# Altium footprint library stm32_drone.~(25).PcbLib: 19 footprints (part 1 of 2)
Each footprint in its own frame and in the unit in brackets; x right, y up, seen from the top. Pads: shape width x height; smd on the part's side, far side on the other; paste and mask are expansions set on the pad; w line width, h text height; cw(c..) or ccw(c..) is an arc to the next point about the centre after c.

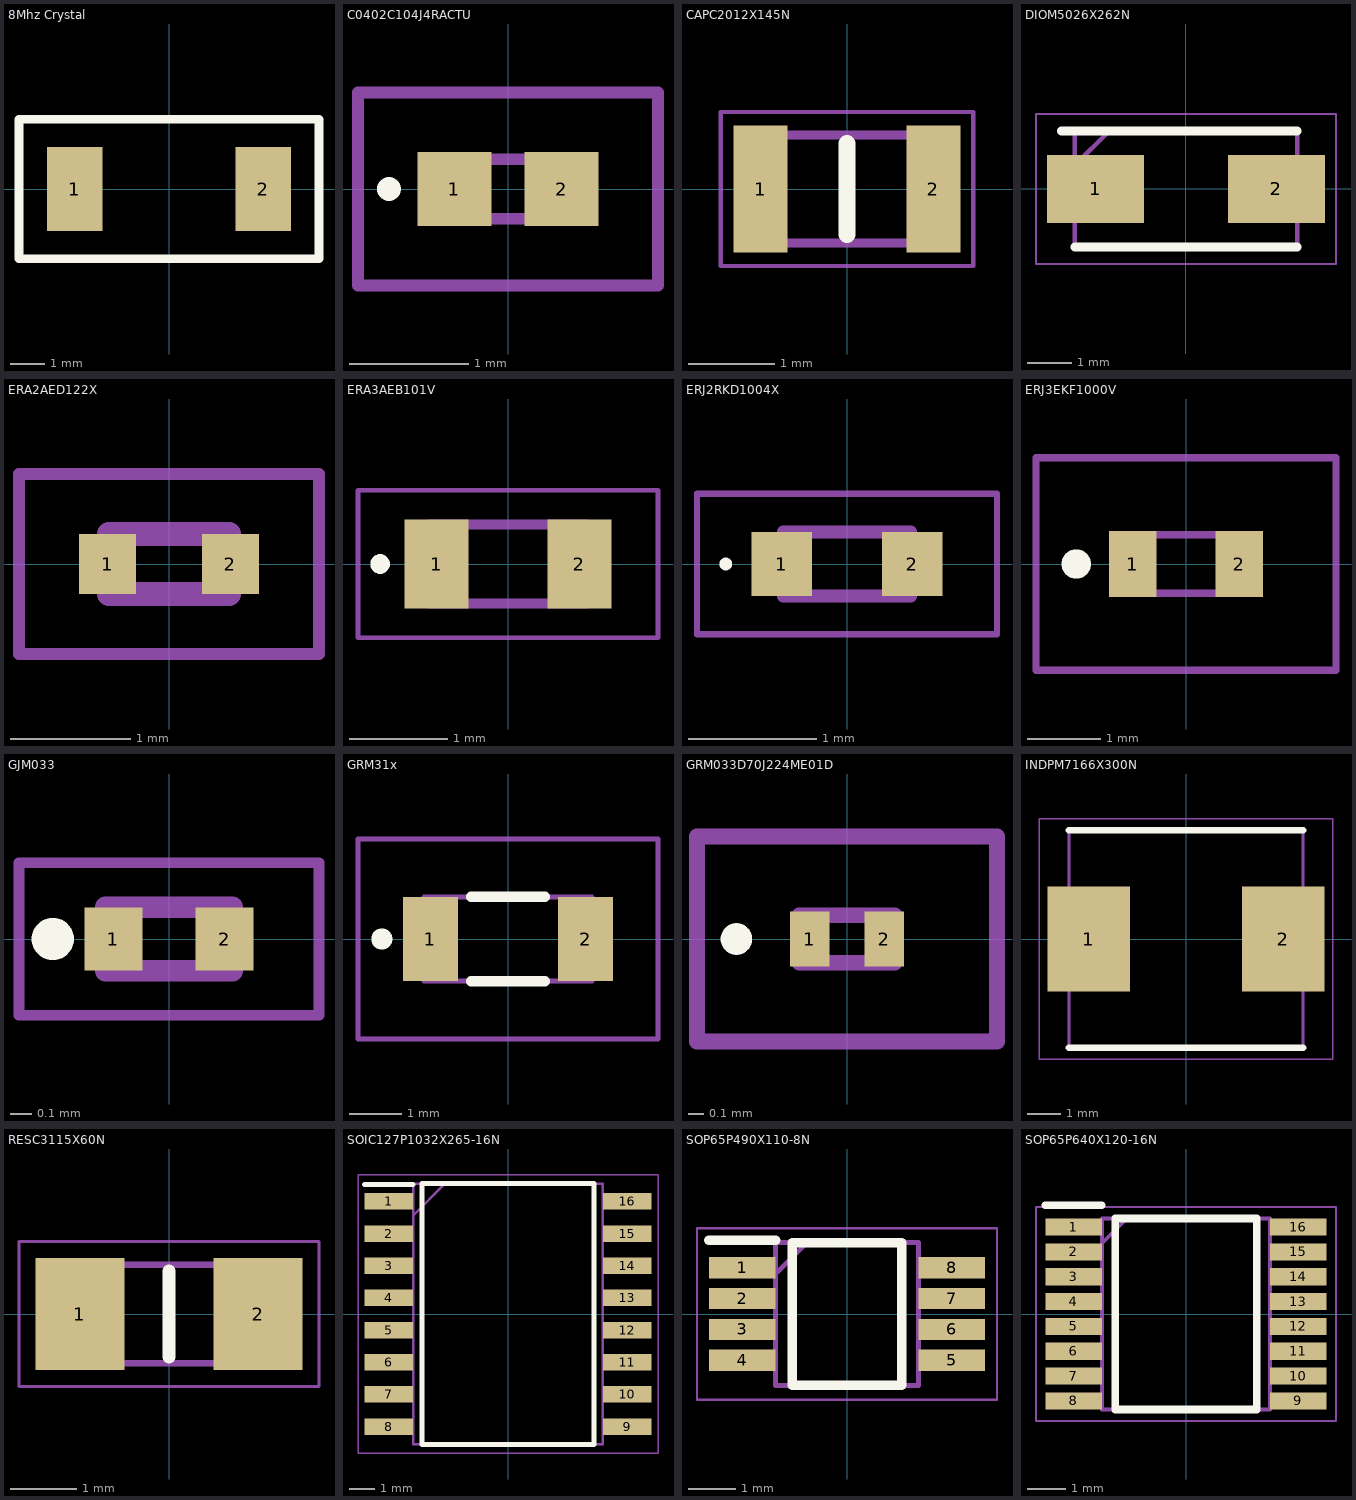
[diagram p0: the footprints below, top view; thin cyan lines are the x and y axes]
## 8Mhz Crystal [mm]
pads (2):
  rect 1.6x2.4 smd: 1(-2.7,0) 2(2.7,0)
Top Overlay:
  lines w0.25: -4.3,-2 -4.3,0 -4.3,2 4.3,2 4.3,-2 -4.3,-2
3D body "XTAL_H130A_RAL.step": height 1.09, standoff 0, extent -2.864,-2.089 2.864,2.089

## C0402C104J4RACTU [mm]
pads (2):
  rect 0.62x0.62 smd: 1(-0.45,0) 2(0.45,0)
Top Overlay:
  lines w0.1: -1,-0.05 cw(c-1,0) -1,0.05 cw(c-1,0) -1,-0.05
Mechanical 13:
  lines w0.1: -0.5,-0.25 0.5,-0.25 0.5,0.25 -0.5,0.25 -0.5,-0.25
Mechanical 15:
  lines w0.1: -1.26,-0.81 1.26,-0.81 1.26,0.81 -1.26,0.81 -1.26,-0.81
3D body "C0402C102J5GECTU.stp": height 0.55, standoff 0, extent -0.52,-0.28 0.53,0.27

## CAPC2012X145N [mm]
pads (2):
  rect 0.62x1.47 smd: 1(-1,0) 2(1,0)
Top Overlay:
  lines w0.2: 0,-0.525 0,0.525
Mechanical 13:
  lines w0.1: -1,-0.625 1,-0.625 1,0.625 -1,0.625 -1,-0.625
Mechanical 15:
  lines w0.05: -1.46,-0.89 1.46,-0.89 1.46,0.89 -1.46,0.89 -1.46,-0.89
3D body "C2012X5R1V226M125AC.stp": height 1.25, standoff 0, extent -1,-0.8 1,0.8

## DIOM5026X262N [mm]
pads (2):
  rect 2.2x1.55 smd: 1(-2.05,0) 2(2.05,0)
Top Overlay:
  lines w0.2: -2.825,1.312 2.52,1.312 ; -2.52,-1.312 2.52,-1.312
Mechanical 13:
  lines w0.1: -2.52,0.538 -1.745,1.312 ; -2.52,-1.312 2.52,-1.312 2.52,1.312 -2.52,1.312 -2.52,-1.312
Mechanical 15:
  lines w0.05: -3.4,-1.7 3.4,-1.7 3.4,1.7 -3.4,1.7 -3.4,-1.7
3D body "SS14.stp": height 2.62, standoff 0, extent -2.52,-1.312 2.52,1.312

## ERA2AED122X [mm]
pads (2):
  rect 0.475x0.5 smd: 1(-0.512,0) 2(0.512,0)
Mechanical 13:
  lines w0.2: -0.5,-0.25 0.5,-0.25 0.5,0.25 -0.5,0.25 -0.5,-0.25
Mechanical 15:
  lines w0.1: -1.25,-0.75 1.25,-0.75 1.25,0.75 -1.25,0.75 -1.25,-0.75
3D body "ERA-2AEB4990X.stp": height 0.35, standoff 0, extent -0.5,-0.25 0.5,0.25
3D body "0402_PAN.step": height 0.41, standoff 0, extent -0.546,-0.305 0.546,0.305

## ERA3AEB101V [mm]
pads (2):
  rect 0.65x0.9 smd: 1(-0.725,0) 2(0.725,0)
Top Overlay:
  lines w0.1: -1.3,-0.05 cw(c-1.3,0) -1.3,0.05 cw(c-1.3,0) -1.3,-0.05
Mechanical 13:
  lines w0.1: -0.8,-0.4 0.8,-0.4 0.8,0.4 -0.8,0.4 -0.8,-0.4
Mechanical 15:
  lines w0.05: -1.525,-0.75 1.525,-0.75 1.525,0.75 -1.525,0.75 -1.525,-0.75
3D body "ERA-3AEB333V.stp": height 0.45, standoff 0, extent -0.8,-0.4 0.8,0.4

## ERJ2RKD1004X [mm]
pads (2):
  rect 0.475x0.5 smd: 1(-0.512,0) 2(0.512,0)
Top Overlay:
  lines w0.05: -0.95,-0.025 cw(c-0.95,0) -0.95,0.025 cw(c-0.95,0) -0.95,-0.025
Mechanical 13:
  lines w0.1: -0.5,-0.25 0.5,-0.25 0.5,0.25 -0.5,0.25 -0.5,-0.25
Mechanical 15:
  lines w0.05: -1.175,-0.55 1.175,-0.55 1.175,0.55 -1.175,0.55 -1.175,-0.55
3D body "ERJ-2RKF2002X.stp": height 0.35, standoff 0, extent -0.5,-0.25 0.5,0.25

## ERJ3EKF1000V [mm]
pads (2):
  rect 0.65x0.9 smd: 1(-0.725,0) 2(0.725,0)
Top Overlay:
  lines w0.2: -1.5,-0.1 cw(c-1.5,0) -1.5,0.1 cw(c-1.5,0) -1.5,-0.1
Mechanical 13:
  lines w0.1: -0.8,-0.4 0.8,-0.4 0.8,0.4 -0.8,0.4 -0.8,-0.4
Mechanical 15:
  lines w0.1: -2.05,-1.45 2.05,-1.45 2.05,1.45 -2.05,1.45 -2.05,-1.45
3D body "ERJ-3GEYJ244V.stp": height 0.45, standoff 0, extent -0.8,-0.4 0.8,0.4

## GJM033 [mm]
pads (2):
  rect 0.275x0.3 smd: 1(-0.263,0) 2(0.263,0)
Top Overlay:
  lines w0.1: -0.55,-0.05 cw(c-0.55,0) -0.55,0.05 cw(c-0.55,0) -0.55,-0.05
Mechanical 13:
  lines w0.1: -0.3,-0.15 0.3,-0.15 0.3,0.15 -0.3,0.15 -0.3,-0.15
Mechanical 15:
  lines w0.05: -0.71,-0.36 0.71,-0.36 0.71,0.36 -0.71,0.36 -0.71,-0.36
3D body "GJM0335C1E2R0BB01D.stp": height 0.33, standoff 0, extent -0.3,-0.15 0.3,0.15

## GRM31x [mm]
pads (2):
  rect 1.05x1.6 smd: 1(-1.475,0) 2(1.475,0)
Top Overlay:
  lines w0.2: -0.7,-0.8 0.7,-0.8 ; -0.7,0.8 0.7,0.8 ; -2.4,-0.1 cw(c-2.4,0) -2.4,0.1 cw(c-2.4,0) -2.4,-0.1
Mechanical 13:
  lines w0.1: -1.6,-0.8 1.6,-0.8 1.6,0.8 -1.6,0.8 -1.6,-0.8
Mechanical 15:
  lines w0.1: -2.854,-1.902 2.854,-1.902 2.854,1.902 -2.854,1.902 -2.854,-1.902
3D body "GRM31CR60J107MEA8K.stp": height 1, standoff 0, extent -1.6,-0.8 1.6,0.8

## GRM033D70J224ME01D [mm]
pads (2):
  rect 0.25x0.35 smd: 1(-0.237,0) 2(0.237,0)
Top Overlay:
  lines w0.1: -0.7,-0.05 cw(c-0.7,0) -0.7,0.05 cw(c-0.7,0) -0.7,-0.05
Mechanical 13:
  lines w0.1: -0.3,-0.15 0.3,-0.15 0.3,0.15 -0.3,0.15 -0.3,-0.15
Mechanical 15:
  lines w0.1: -0.95,-0.65 0.95,-0.65 0.95,0.65 -0.95,0.65 -0.95,-0.65
3D body "GRM033C80J104KE15D.stp": height 0.3, standoff 0, extent -0.3,-0.15 0.3,0.15

## INDPM7166X300N [mm]
pads (2):
  rect 2.5x3.2 smd: 1(-2.95,0) 2(2.95,0)
Top Overlay:
  lines w0.2: -3.55,-3.3 3.55,-3.3 ; -3.55,3.3 3.55,3.3
Mechanical 13:
  lines w0.1: -3.55,-3.3 -3.55,3.3 3.55,3.3 3.55,-3.3 -3.55,-3.3
Mechanical 15:
  lines w0.05: -4.45,-3.65 -4.45,3.65 4.45,3.65 4.45,-3.65 -4.45,-3.65
3D body "ECS-MPIL0630-220MC.stp": height 3, standoff 0, extent -3.55,-3.3 3.55,3.3

## RESC3115X60N [mm]
pads (2):
  rect 1.35x1.7 smd: 1(-1.35,0) 2(1.35,0)
Top Overlay:
  lines w0.2: 0,-0.65 0,0.65
Mechanical 13:
  lines w0.1: -1.55,-0.75 -1.55,0.75 1.55,0.75 1.55,-0.75 -1.55,-0.75
Mechanical 15:
  lines w0.05: -2.275,-1.1 -2.275,1.1 2.275,1.1 2.275,-1.1 -2.275,-1.1
3D body "RNCP1206FTD10K0.stp": height 0.5, standoff 0, extent -1.554,-0.746 1.546,0.754

## SOIC127P1032X265-16N [mm]
pads (16):
  rect 1.925x0.65 smd: 1(-4.712,4.445) 2(-4.712,3.175) 3(-4.712,1.905) 4(-4.712,0.635) 5(-4.712,-0.635) 6(-4.712,-1.905) 7(-4.712,-3.175) 8(-4.712,-4.445) 9(4.712,-4.445) 10(4.712,-3.175) 11(4.712,-1.905) 12(4.712,-0.635) 13(4.712,0.635) 14(4.712,1.905) 15(4.712,3.175) 16(4.712,4.445)
Top Overlay:
  lines w0.2: -5.675,5.12 -3.75,5.12 ; -3.4,-5.15 3.4,-5.15 3.4,5.15 -3.4,5.15 -3.4,-5.15
Mechanical 13:
  lines w0.1: -3.75,3.88 -2.48,5.15 ; -3.75,-5.15 3.75,-5.15 3.75,5.15 -3.75,5.15 -3.75,-5.15
Mechanical 15:
  lines w0.05: -5.925,-5.5 5.925,-5.5 5.925,5.5 -5.925,5.5 -5.925,-5.5
3D body "IR2110STRPBF.stp": height 2.65, standoff 0, extent -5.162,-5.15 5.162,5.15

## SOP65P490X110-8N [mm]
pads (8):
  rect 1.4x0.45 smd: 1(-2.2,0.975) 2(-2.2,0.325) 3(-2.2,-0.325) 4(-2.2,-0.975) 5(2.2,-0.975) 6(2.2,-0.325) 7(2.2,0.325) 8(2.2,0.975)
Top Overlay:
  lines w0.2: -2.9,1.55 -1.5,1.55 ; -1.15,-1.5 -1.15,1.5 1.15,1.5 1.15,-1.5 -1.15,-1.5
Mechanical 13:
  lines w0.1: -1.5,0.85 -0.85,1.5 ; -1.5,-1.5 -1.5,1.5 1.5,1.5 1.5,-1.5 -1.5,-1.5
Mechanical 15:
  lines w0.05: -3.15,-1.8 -3.15,1.8 3.15,1.8 3.15,-1.8 -3.15,-1.8
3D body "LM3485MMX_NOPB.stp": height 1.1, standoff 0, extent -2.451,-1.499 2.451,1.499

## SOP65P640X120-16N [mm]
pads (16):
  rect 1.475x0.45 smd: 1(-2.938,2.275) 2(-2.938,1.625) 3(-2.938,0.975) 4(-2.938,0.325) 5(-2.938,-0.325) 6(-2.938,-0.975) 7(-2.938,-1.625) 8(-2.938,-2.275) 9(2.938,-2.275) 10(2.938,-1.625) 11(2.938,-0.975) 12(2.938,-0.325) 13(2.938,0.325) 14(2.938,0.975) 15(2.938,1.625) 16(2.938,2.275)
Top Overlay:
  lines w0.2: -3.675,2.85 -2.2,2.85 ; -1.85,-2.5 1.85,-2.5 1.85,2.5 -1.85,2.5 -1.85,-2.5
Mechanical 13:
  lines w0.1: -2.2,1.85 -1.55,2.5 ; -2.2,-2.5 2.2,-2.5 2.2,2.5 -2.2,2.5 -2.2,-2.5
Mechanical 15:
  lines w0.05: -3.925,-2.8 3.925,-2.8 3.925,2.8 -3.925,2.8 -3.925,-2.8
3D body "MIC4606-2YTS-TR.stp": height 1.2, standoff 0, extent -3.2,-2.5 3.2,2.5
